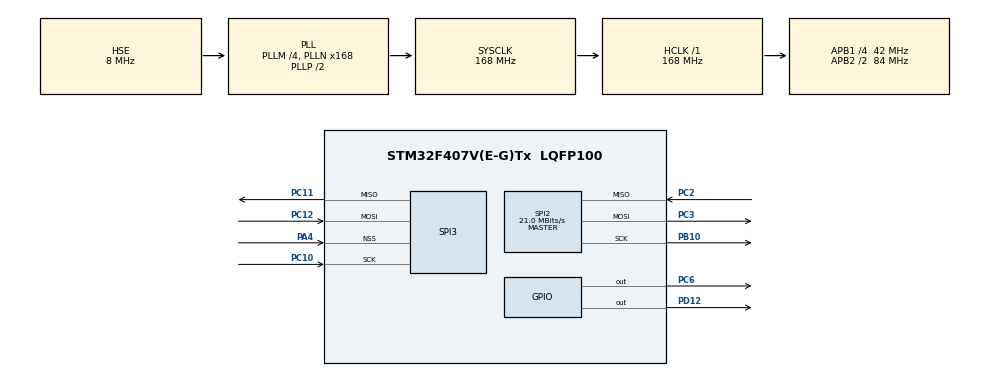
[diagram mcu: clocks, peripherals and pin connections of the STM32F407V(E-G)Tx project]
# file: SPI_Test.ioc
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Dma.Request0=SPI3_RX
Dma.SPI3_RX.0.Channel=DMA_CHANNEL_0
Dma.SPI3_RX.0.Direction=DMA_PERIPH_TO_MEMORY
Dma.SPI3_RX.0.FIFOMode=DMA_FIFOMODE_DISABLE
Dma.SPI3_RX.0.Instance=DMA1_Stream0
Dma.SPI3_RX.0.MemDataAlignment=DMA_MDATAALIGN_BYTE
Dma.SPI3_RX.0.MemInc=DMA_MINC_ENABLE
Dma.SPI3_RX.0.Mode=DMA_CIRCULAR
Dma.SPI3_RX.0.PeriphDataAlignment=DMA_PDATAALIGN_BYTE
Dma.SPI3_RX.0.PeriphInc=DMA_PINC_DISABLE
Dma.SPI3_RX.0.Priority=DMA_PRIORITY_VERY_HIGH
Mcu.Family=STM32F4
Mcu.Name=STM32F407V(E-G)Tx
Mcu.Package=LQFP100
NVIC.DMA1_Stream0_IRQn=true\:0\:0\:false\:false\:true
NVIC.PriorityGroup=NVIC_PRIORITYGROUP_4
NVIC.SPI2_IRQn=true\:1\:0\:true\:false\:true
NVIC.SPI3_IRQn=true\:2\:0\:true\:false\:true
PA4.Mode=NSS_Signal_Hard_Input
PA4.Signal=SPI3_NSS
PB10.Mode=Full_Duplex_Master
PB10.Signal=SPI2_SCK
PC10.Mode=Full_Duplex_Slave
PC10.Signal=SPI3_SCK
PC11.Mode=Full_Duplex_Slave
PC11.Signal=SPI3_MISO
PC12.Mode=Full_Duplex_Slave
PC12.Signal=SPI3_MOSI
PC2.Mode=Full_Duplex_Master
PC2.Signal=SPI2_MISO
PC3.Mode=Full_Duplex_Master
PC3.Signal=SPI2_MOSI
PC6.GPIO_ModeDefaultOutputPP=GPIO_MODE_OUTPUT_PP
PC6.GPIO_PuPd=GPIO_NOPULL
PC6.GPIO_Speed=GPIO_SPEED_FREQ_VERY_HIGH
PC6.PinState=GPIO_PIN_RESET
PC6.Signal=GPIO_Output
PD12.GPIO_ModeDefaultOutputPP=GPIO_MODE_OUTPUT_PP
PD12.GPIO_PuPd=GPIO_NOPULL
PD12.GPIO_Speed=GPIO_SPEED_FREQ_VERY_HIGH
PD12.PinState=GPIO_PIN_RESET
PD12.Signal=GPIO_Output
PH0-OSC_IN.Mode=HSE-External-Oscillator
PH0-OSC_IN.Signal=RCC_OSC_IN
PH1-OSC_OUT.Mode=HSE-External-Oscillator
PH1-OSC_OUT.Signal=RCC_OSC_OUT
ProjectManager.HeapSize=0x200
ProjectManager.StackSize=0x400
ProjectManager.TargetToolchain=MDK-ARM V5
RCC.48MHZClocksFreq_Value=84000000
RCC.AHBFreq_Value=168000000
RCC.APB1CLKDivider=RCC_HCLK_DIV4
RCC.APB1Freq_Value=42000000
RCC.APB1TimCLKDivider=1
RCC.APB1TimFreq_Value=42000000
RCC.APB2CLKDivider=RCC_HCLK_DIV2
RCC.APB2Freq_Value=84000000
RCC.APB2TimCLKDivider=1
RCC.APB2TimFreq_Value=84000000
RCC.CortexFreq_Value=168000000
RCC.HCLKFreq_Value=168000000
RCC.HSE_VALUE=8000000
RCC.HSI_VALUE=16000000
RCC.LSE_VALUE=32768
RCC.PLLM=4
RCC.PLLN=168
RCC.PLLSourceVirtual=RCC_PLLSOURCE_HSE
RCC.SYSCLKFreq_VALUE=168000000
RCC.SYSCLKSource=RCC_SYSCLKSOURCE_PLLCLK
RCC.VCOOutputFreq_Value=336000000
SPI2.BaudRatePrescaler=SPI_BAUDRATEPRESCALER_2
SPI2.CalculateBaudRate=21.0 MBits/s
SPI2.Mode=SPI_MODE_MASTER
SPI3.CLKPolarity=SPI_POLARITY_HIGH
SPI3.VirtualNSS=VM_NSSHARD
SPI3.VirtualType=VM_SLAVE
board=SPI_Test

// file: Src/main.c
					/*In this project SPI2 is master, SPI3 is slave
					PC2 (SPI2 MISO)  -  PC11 (SPI3 MISO)
					PC3 (SPI2 MOSI)  -  PC12 (SPI3 MOSI)
					PB10(SPI2 SCK)   -  PC10 (SPI3 SCK)
					PC6 (SPI2 NSS pin control by software) - PA4 (SPI3 NSS pin control by hardware)*/

#include "stm32f4xx_hal.h"

SPI_HandleTypeDef hspi2;
SPI_HandleTypeDef hspi3;
DMA_HandleTypeDef hdma_spi3_rx;

#define spi3_enable    HAL_GPIO_WritePin(GPIOC, GPIO_PIN_6, GPIO_PIN_RESET)	//set SPI_NSS low level
#define spi3_disable   HAL_GPIO_WritePin(GPIOC, GPIO_PIN_6, GPIO_PIN_SET)		//set SPI_NSS high level

uint8_t send_data_spi2 = 32, receive_data_spi3 = 3;// , receive_data_spi2 = 2;

void SystemClock_Config(void);
static void MX_GPIO_Init(void);
static void MX_DMA_Init(void);
static void MX_SPI2_Init(void);
static void MX_SPI3_Init(void);

int main(void)
{

  /* Reset of all peripherals, Initializes the Flash interface and the Systick. */
  HAL_Init();

  /* Configure the system clock */
  SystemClock_Config();

  /* Initialize all configured peripherals */
  MX_GPIO_Init();
  MX_DMA_Init();
  MX_SPI2_Init();
  MX_SPI3_Init();

	HAL_SPI_Receive_DMA(&hspi3, &receive_data_spi3, 1);	//spi3 receive data DMA

  /* Infinite loop */
  /* USER CODE BEGIN WHILE */
  while (1)
  {

  }
  /* USER CODE END 3 */
}
		//When user press User Button => Send data
void EXTI0_IRQHandler(void)
{
	spi3_enable;
	HAL_SPI_Transmit_IT(&hspi2, &send_data_spi2, 1); //master send data

	send_data_spi2++;
	HAL_Delay(150);

  HAL_GPIO_EXTI_IRQHandler(GPIO_PIN_0);
}

		//After SPI2 send data, disable SPI3 and blynk led
void HAL_SPI_TxCpltCallback(SPI_HandleTypeDef *hspi)
{
	if(hspi->Instance == hspi2.Instance)
	{
		spi3_disable;

		HAL_GPIO_WritePin(GPIOD, GPIO_PIN_12, GPIO_PIN_SET);
		HAL_Delay(500);
		HAL_GPIO_WritePin(GPIOD, GPIO_PIN_12, GPIO_PIN_RESET);
	}
}

/** System Clock Configuration
*/
void SystemClock_Config(void)
{

  RCC_OscInitTypeDef RCC_OscInitStruct;
  RCC_ClkInitTypeDef RCC_ClkInitStruct;

  __HAL_RCC_PWR_CLK_ENABLE();

  __HAL_PWR_VOLTAGESCALING_CONFIG(PWR_REGULATOR_VOLTAGE_SCALE1);

  RCC_OscInitStruct.OscillatorType = RCC_OSCILLATORTYPE_HSE;
  RCC_OscInitStruct.HSEState = RCC_HSE_ON;
  RCC_OscInitStruct.PLL.PLLState = RCC_PLL_ON;
  RCC_OscInitStruct.PLL.PLLSource = RCC_PLLSOURCE_HSE;
  RCC_OscInitStruct.PLL.PLLM = 4;
  RCC_OscInitStruct.PLL.PLLN = 168;
  RCC_OscInitStruct.PLL.PLLP = RCC_PLLP_DIV2;
  RCC_OscInitStruct.PLL.PLLQ = 4;
  HAL_RCC_OscConfig(&RCC_OscInitStruct);

  RCC_ClkInitStruct.ClockType = RCC_CLOCKTYPE_HCLK|RCC_CLOCKTYPE_SYSCLK
                              |RCC_CLOCKTYPE_PCLK1|RCC_CLOCKTYPE_PCLK2;
  RCC_ClkInitStruct.SYSCLKSource = RCC_SYSCLKSOURCE_PLLCLK;
  RCC_ClkInitStruct.AHBCLKDivider = RCC_SYSCLK_DIV1;
  RCC_ClkInitStruct.APB1CLKDivider = RCC_HCLK_DIV4;
  RCC_ClkInitStruct.APB2CLKDivider = RCC_HCLK_DIV2;
  HAL_RCC_ClockConfig(&RCC_ClkInitStruct, FLASH_LATENCY_5);

  HAL_SYSTICK_Config(HAL_RCC_GetHCLKFreq()/1000);

  HAL_SYSTICK_CLKSourceConfig(SYSTICK_CLKSOURCE_HCLK);

  /* SysTick_IRQn interrupt configuration */
  HAL_NVIC_SetPriority(SysTick_IRQn, 0, 0);

}

/* SPI2 init function */
void MX_SPI2_Init(void)
{

  hspi2.Instance = SPI2;
  hspi2.Init.Mode = SPI_MODE_MASTER;
  hspi2.Init.Direction = SPI_DIRECTION_2LINES;
  hspi2.Init.DataSize = SPI_DATASIZE_8BIT;
  hspi2.Init.CLKPolarity = SPI_POLARITY_LOW;
  hspi2.Init.CLKPhase = SPI_PHASE_1EDGE;
  hspi2.Init.NSS = SPI_NSS_SOFT;
  hspi2.Init.BaudRatePrescaler = SPI_BAUDRATEPRESCALER_2;
  hspi2.Init.FirstBit = SPI_FIRSTBIT_MSB;
  hspi2.Init.TIMode = SPI_TIMODE_DISABLE;
  hspi2.Init.CRCCalculation = SPI_CRCCALCULATION_DISABLE;
  hspi2.Init.CRCPolynomial = 10;
  HAL_SPI_Init(&hspi2);

}

/* SPI3 init function */
void MX_SPI3_Init(void)
{

  hspi3.Instance = SPI3;
  hspi3.Init.Mode = SPI_MODE_SLAVE;
  hspi3.Init.Direction = SPI_DIRECTION_2LINES;
  hspi3.Init.DataSize = SPI_DATASIZE_8BIT;
  hspi3.Init.CLKPolarity = SPI_POLARITY_HIGH;
  hspi3.Init.CLKPhase = SPI_PHASE_1EDGE;
  hspi3.Init.NSS = SPI_NSS_HARD_INPUT;
  hspi3.Init.FirstBit = SPI_FIRSTBIT_MSB;
  hspi3.Init.TIMode = SPI_TIMODE_DISABLE;
  hspi3.Init.CRCCalculation = SPI_CRCCALCULATION_DISABLE;
  hspi3.Init.CRCPolynomial = 10;
  HAL_SPI_Init(&hspi3);

}

void MX_DMA_Init(void)
{
  /* DMA controller clock enable */
  __HAL_RCC_DMA1_CLK_ENABLE();

  /* DMA interrupt init */
  /* DMA1_Stream0_IRQn interrupt configuration */
  HAL_NVIC_SetPriority(DMA1_Stream0_IRQn, 0, 0);
  HAL_NVIC_EnableIRQ(DMA1_Stream0_IRQn);

}

/** Configure pins as
        * Analog
        * Input
        * Output
        * EVENT_OUT
        * EXTI
*/
void MX_GPIO_Init(void)
{

  GPIO_InitTypeDef GPIO_InitStruct;

  /* GPIO Ports Clock Enable */
  __HAL_RCC_GPIOH_CLK_ENABLE();
  __HAL_RCC_GPIOC_CLK_ENABLE();
  __HAL_RCC_GPIOA_CLK_ENABLE();
  __HAL_RCC_GPIOB_CLK_ENABLE();
  __HAL_RCC_GPIOD_CLK_ENABLE();

  /*Configure GPIO pin Output Level */
  HAL_GPIO_WritePin(GPIOD, GPIO_PIN_12, GPIO_PIN_RESET);

  /*Configure GPIO pin Output Level */
  HAL_GPIO_WritePin(GPIOC, GPIO_PIN_6, GPIO_PIN_RESET);

  /*Configure GPIO pin : PD12, PD13 */
  GPIO_InitStruct.Pin = GPIO_PIN_12|GPIO_PIN_13;
  GPIO_InitStruct.Mode = GPIO_MODE_OUTPUT_PP;
  GPIO_InitStruct.Pull = GPIO_NOPULL;
  GPIO_InitStruct.Speed = GPIO_SPEED_FREQ_VERY_HIGH;
  HAL_GPIO_Init(GPIOD, &GPIO_InitStruct);

  /*Configure GPIO pin : PC6 */
  GPIO_InitStruct.Pin = GPIO_PIN_6;
  GPIO_InitStruct.Mode = GPIO_MODE_OUTPUT_PP;
  GPIO_InitStruct.Pull = GPIO_NOPULL;
  GPIO_InitStruct.Speed = GPIO_SPEED_FREQ_VERY_HIGH;
  HAL_GPIO_Init(GPIOC, &GPIO_InitStruct);

	  /*Configure GPIO pin : PA0 */
  GPIO_InitStruct.Pin = GPIO_PIN_0;
  GPIO_InitStruct.Mode = GPIO_MODE_IT_RISING_FALLING ;
  GPIO_InitStruct.Pull = GPIO_NOPULL;
  GPIO_InitStruct.Speed = GPIO_SPEED_FREQ_VERY_HIGH;
  HAL_GPIO_Init(GPIOA, &GPIO_InitStruct);

	/*EXTI init*/
	HAL_NVIC_EnableIRQ(EXTI0_IRQn);
	HAL_NVIC_SetPriority(EXTI0_IRQn, 3, 0);

}

/************************ (C) COPYRIGHT STMicroelectronics *****END OF FILE****/
